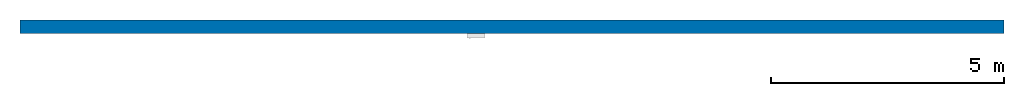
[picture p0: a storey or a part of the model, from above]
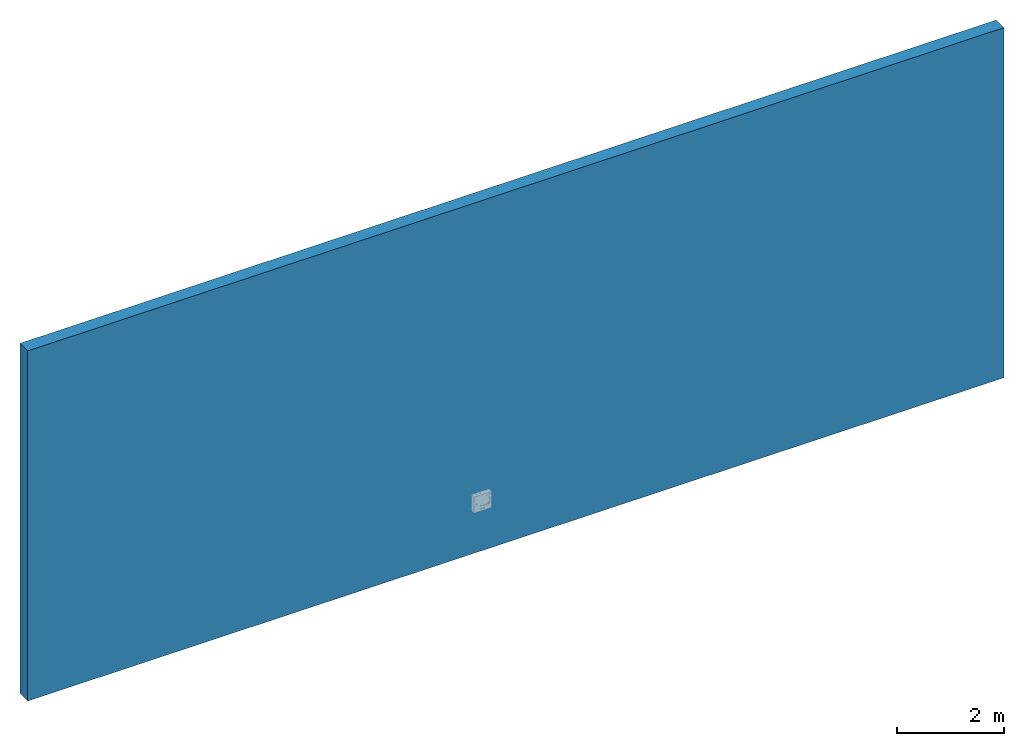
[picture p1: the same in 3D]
Properties of the parts of a building model (IFC2X3)

# File
Description: ViewDefinition [CoordinationView]
File name: Project Number
Time: 2014-10-31T08:35:02
Written by: The EXPRESS Data Manager Version 5.01.0100.02.64mod : 6 Jun 2012
Made in: 20140709_2115(x64) - Exporter 2014.0.2014.0709 - Default UI
Comment: STEP Physical File produced by: The EXPRESS Data Manager Version 5.01.0100.02.64mod : 6 Jun 2012 * Module: EDMstepFileFactory/EDMstandAlone * Creation date: Fri Oct 31 08:35:02 2014 * Host: BIM-HP * Database: C:\Users\dcole\AppData\Local\Temp\{094924D8-CAA2-4B1B-B7A2-B05955C44841}\ifc * Database version: 5507 * Database creation date: Fri Oct 31 08:35:01 2014 * Schema: IFC2X3 * Model: DataRepository.ifc * Model creation date: Fri Oct 31 08:35:02 2014 * Header model: DataRepository.ifc_HeaderModel * Header model creation date: Fri Oct 31 08:35:02 2014 * EDMuser: sdai-user * EDMgroup: sdai-group * License ID and type: 5605 : Permanent license. Expiry date: * EDMstepFileFactory options: 020000

# IfcProject, Project Number
LongName: Project Name; Phase: Project Status

# IfcSite, Default
RefLatitude: 51, 30, 0, 549316; RefLongitude: 0, -7, -34, -450321; RefElevation: 0 mm

# IfcBuilding
Pset_BuildingCommon - NumberOfStoreys: 1
Other - Project Issue Date: Issue Date; Project Number: Project Number; Project Status: Project Status; Client Name: Owner; Project Name: Project Name; Project Address: Enter address here

# IfcBuildingStorey, Level 0
LongName: Level 0; Elevation: 0 mm
Constraints - Elevation Base: Project Base Point; Elevation: 0 mm
Graphics - Line Pattern: Centre; Line Weight: 1; Symbol at End 2 Default: no; Symbol: Level Head - Circle: Level Head - Circle; Color: 0; Symbol at End 1 Default: yes
Identity Data - Name: Level 0; Structural: no; Building Story: yes
Dimensions - Computation Height: 0 mm

# IfcBuildingElementProxy: Notifier by Honeywell ID60 Single Loop Intelligent Fire Alarm Panel 002-456, ID60:Notifier by Honeywell ID60 Single Loop Intelligent Fire Alarm Panel 002-456:217626
In: Level 0
Material: Render Material 255-255-255, Light Gray, Polypropylene, Platinum
Constraints - Offset: 996.079 mm; Level: Level: Level 0; Moves With Nearby Elements: no; Host: Level : Level 0
Phasing - Phase Created: New Construction
Identity Data - Mark: 1; Manufacturer: Notifier by Honeywell; Assembly Code: D4090900; Assembly Description: Misc. Other Fire Protection Systems; URL: www.notifierfiresystems.co.uk; Product Code: 002-456; Type Comments: Single Loop Intelligent Fire Alarm Panel; Model: ID60; Description: Fire Alarm Panel
Pset_ManufacturerTypeInformation - Manufacturer: Notifier by Honeywell
Pset_BuildingElementProxyCommon - Reference: Notifier by Honeywell ID60 Single Loop Intelligent Fire Alarm Panel 002-456
Title Text - Tel No.: +44 (0) 1273 897000; Fax No.: +44 (0) 1273 376894; Address line 1: Caburn House, Brooks Road, Lewes, E. Sussex BN7 2BY, UK; Email: sales@notifierfiresystems.co.uk

# IfcWallStandardCase: Basic Wall:Cav - 102 75i 100 p - Lwt, Basic Wall:Cav - 102 75i 100 p - Lwt:216686
In: Level 0
Type - PredefinedType: STANDARD; Material: Brick, Common 102.5 mm, Fiberglass Batt 75 mm, Concrete Masonry Units 100 mm, Gypsum Wall Board 12.5 mm
Type - Construction - Width: 290 mm; Function: Exterior; Wrapping at Inserts: Both
Type - Identity Data - Keynote: F10
Type - Analytical Properties - Roughness: 3; Thermal mass: 298413; Thermal Resistance (R): 4.23334; Absorptance: 0.7; Heat Transfer Coefficient (U): 0.23622
Type - Graphics - Coarse Scale Fill Pattern: Solid fill; Coarse Scale Fill Color: 12632256
Type - Materials and Finishes - Structural Material: Concrete Masonry Units
Constraints - Base Constraint: Level: Level 0; Base Extension Distance: 0 mm; Base is Attached: no; Base Offset: 0 mm; Room Bounding: yes; Top Offset: 0 mm; Location Line: Wall Centerline; Unconnected Height: 8000 mm; Related to Mass: no; Top Extension Distance: 0 mm; Top is Attached: no
Structural - Structural Usage: Non-bearing; Structural: no; Enable Analytical Model: no
Phasing - Phase Created: New Construction
Dimensions - Area: 168.8 m2; Volume: 48.952 m3; Length: 21100 mm
Pset_WallCommon - Reference: Cav - 102 75i 100 p - Lwt; LoadBearing: no; ExtendToStructure: no; IsExternal: yes; ThermalTransmittance: 0.23622 kg/K/s3
